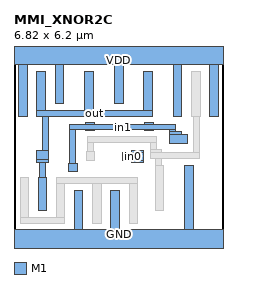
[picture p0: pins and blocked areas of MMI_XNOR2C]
MACRO MMI_XNOR2C
	CLASS CORE ;
	FOREIGN MMI_XNOR2C 0 0 ;
	SIZE 6.82 BY 6.2 ;
	SYMMETRY X Y ;
	SITE CORE1 ;
	PIN out
		DIRECTION output ;
		USE SIGNAL ;
		PORT
			LAYER M1 ;
			RECT 0.75 4.3 1.03 5.58 ;
			LAYER M1 ;
			RECT 2.315 4.3 2.595 5.58 ;
			LAYER M1 ;
			RECT 4.24 4.3 4.52 5.58 ;
			LAYER M1 ;
			RECT 0.75 4.11 4.52 4.3 ;
			LAYER M1 ;
			RECT 0.945 2.98 1.135 4.11 ;
			LAYER M1 ;
			RECT 0.74 2.695 1.135 2.98 ;
			LAYER M1 ;
			RECT 0.74 2.6 1.12 2.695 ;
			LAYER M1 ;
			RECT 0.845 2.09 1.04 2.6 ;
			LAYER M1 ;
			RECT 0.79 1.03 1.07 2.09 ;
		END
		AntennaDiffArea 2.7104 ;
	END out
	PIN in1
		DIRECTION input ;
		USE SIGNAL ;
		PORT
			LAYER M1 ;
			RECT 2.345 3.845 2.625 3.91 ;
			LAYER M1 ;
			RECT 4.27 3.85 4.55 3.91 ;
			LAYER M1 ;
			RECT 4.27 3.845 5.275 3.85 ;
			LAYER M1 ;
			RECT 1.825 3.655 5.275 3.845 ;
			LAYER M1 ;
			RECT 1.825 2.57 2.015 3.655 ;
			LAYER M1 ;
			RECT 2.345 3.63 2.625 3.655 ;
			LAYER M1 ;
			RECT 4.27 3.63 4.55 3.655 ;
			LAYER M1 ;
			RECT 5.08 3.6 5.275 3.655 ;
			LAYER M1 ;
			RECT 5.08 3.5 5.46 3.6 ;
			LAYER M1 ;
			RECT 5.08 3.22 5.655 3.5 ;
			LAYER M1 ;
			RECT 1.78 2.29 2.06 2.57 ;
		END
		AntennaGateArea 1.848 ;
	END in1
	PIN GND
		DIRECTION inout ;
		USE GROUND ;
		PORT
			LAYER M1 ;
			RECT 1.97 0.42 2.25 1.68 ;
			LAYER M1 ;
			RECT 3.15 0.42 3.43 1.68 ;
			LAYER M1 ;
			RECT 5.57 0.42 5.85 2.505 ;
			LAYER M1 ;
			RECT 0 -0.42 6.82 0.42 ;
		END
	END GND
	PIN VDD
		DIRECTION inout ;
		USE POWER ;
		PORT
			LAYER M1 ;
			RECT 0 5.78 6.82 6.62 ;
			LAYER M1 ;
			RECT 0.16 4.11 0.44 5.78 ;
			LAYER M1 ;
			RECT 1.34 4.52 1.62 5.78 ;
			LAYER M1 ;
			RECT 3.28 4.52 3.56 5.78 ;
			LAYER M1 ;
			RECT 5.2 4.11 5.48 5.78 ;
			LAYER M1 ;
			RECT 6.38 4.11 6.66 5.78 ;
		END
	END VDD
	PIN in0
		DIRECTION input ;
		USE SIGNAL ;
		PORT
			LAYER M1 ;
			RECT 3.84 2.93 4.22 2.98 ;
			LAYER M1 ;
			RECT 3.53 2.65 4.22 2.93 ;
			LAYER M1 ;
			RECT 3.84 2.6 4.22 2.65 ;
		END
		AntennaGateArea 1.848 ;
	END in0
	OBS
		LAYER M1 ;
		RECT 5.79 4.11 6.07 5.58 ;
		LAYER M1 ;
		RECT 2.4 3.235 4.665 3.43 ;
		LAYER M1 ;
		RECT 2.4 2.94 2.595 3.235 ;
		LAYER M1 ;
		RECT 4.47 3.005 4.665 3.235 ;
		LAYER M1 ;
		RECT 2.36 2.66 2.64 2.94 ;
		LAYER M1 ;
		RECT 4.47 2.905 4.8 3.005 ;
		LAYER M1 ;
		RECT 5.87 2.905 6.06 4.11 ;
		LAYER M1 ;
		RECT 4.47 2.71 6.06 2.905 ;
		LAYER M1 ;
		RECT 4.61 2.505 4.8 2.71 ;
		LAYER M1 ;
		RECT 0.2 0.815 0.48 2.09 ;
		LAYER M1 ;
		RECT 1.38 1.9 4.035 2.09 ;
		LAYER M1 ;
		RECT 1.38 0.815 1.66 1.9 ;
		LAYER M1 ;
		RECT 0.2 0.62 1.66 0.815 ;
		LAYER M1 ;
		RECT 2.56 0.62 2.84 1.9 ;
		LAYER M1 ;
		RECT 3.755 0.62 4.035 1.9 ;
		LAYER M1 ;
		RECT 4.61 1.035 4.89 2.505 ;
	END
END MMI_XNOR2C
